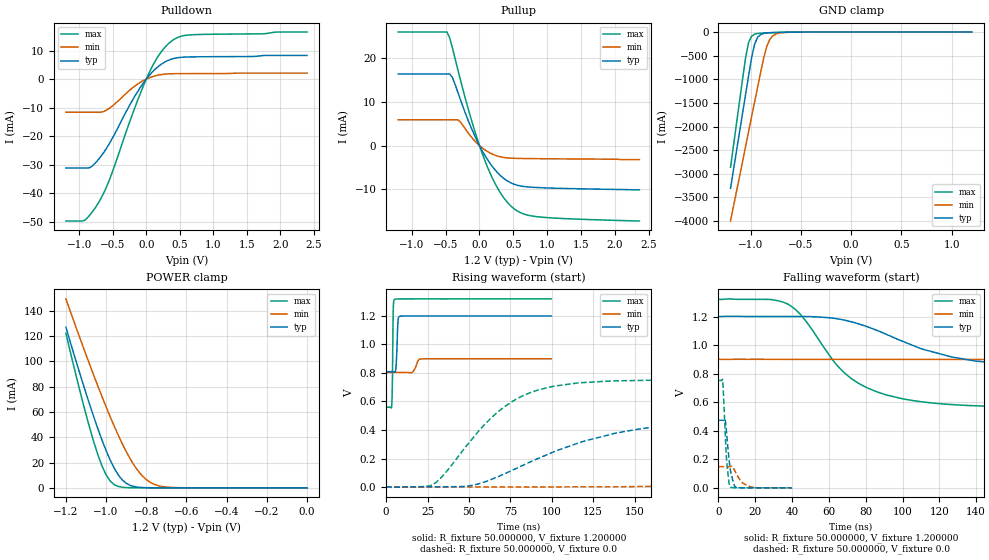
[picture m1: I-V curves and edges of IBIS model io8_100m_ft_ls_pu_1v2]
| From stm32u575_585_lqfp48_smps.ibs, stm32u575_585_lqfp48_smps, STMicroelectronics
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|   Model io8_100m_ft_ls_pu_1v2
[Model]  io8_100m_ft_ls_pu_1v2
Model_type I/O
Polarity   Non-Inverting
Enable   Active-Low
Vinl =   0.360000V
Vinh =   0.840000V
Vmeas =  0.600000V
Cref =   50.000000pF
Rref =   100.000000M
Vref =   0.0V
C_comp   2.947800pF   2.877700pF   2.996100pF
[Temperature Range]   25.000000   0.140000k   -40.000000
[Pullup Reference]   1.200000V   0.900000V   1.320000V
[Pulldown Reference]   0.0V   0.0V   0.0V
[POWER Clamp Reference]   1.200000V   0.900000V   1.320000V
[GND Clamp Reference]   0.0V   0.0V   0.0V
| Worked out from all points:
|   slope of the pulldown table from 0 to 0.18 V, typ, clamps not added: 40.7 ohm
|   slope of the pullup table from 0 to 0.18 V, typ, clamps not added: 39.5 ohm
|   GND clamp passes 1 mA (typ) near -0.51 V on its own axis
|   POWER clamp passes 1 mA (typ) near -0.86 V on its own axis
|   rising waveform, R_fixture 50.000000, V_fixture 1.200000: 20-80 % time 754ps typ, 2.06ns min, 442ps max; typ from 0.809 V to 1.2 V
|   rising waveform, R_fixture 50.000000, V_fixture 0.0: 20-80 % time 67.2ns typ, 167ns min, 37.1ns max; typ from 0.001 V to 0.474 V
|   falling waveform, R_fixture 50.000000, V_fixture 1.200000: 20-80 % time 58ns typ, 150ns min, 31.6ns max; typ from 1.2 V to 0.809 V
|   falling waveform, R_fixture 50.000000, V_fixture 0.0: 20-80 % time 2.49ns typ, 4.76ns min, 1.84ns max; typ from 0.474 V to 0.001 V
[Pulldown]
|Voltage   I(typ)   I(min)   I(max)
-1.2V     -31.16mA   -11.61mA   -49.71mA
-920mV    -31.16mA   -11.61mA   -49.49mA
-840mV    -31mA      -11.61mA   -47.54mA
-720mV    -28.32mA   -11.61mA   -43.58mA
-560mV    -22.95mA   -10.37mA   -35.89mA
-200mV    -7.146mA   -2.964mA   -11.89mA
0V        0A         0A         0A
160mV     4.047mA    1.298mA    7.361mA
360mV     6.869mA    1.87mA     13mA
480mV     7.543mA    1.91mA     14.69mA
640mV     7.765mA    1.923mA    15.46mA
2.4V      8.291mA    2.091mA    16.49mA
[Pullup]
|Voltage   I(typ)   I(min)   I(max)
-1.2V     16.38mA    5.9mA      25.96mA
-480mV    16.38mA    5.9mA      25.96mA
-440mV    16.38mA    5.9mA      24.63mA
-400mV    15.57mA    5.9mA      22.35mA
-320mV    12.21mA    5.9mA      17.37mA
-120mV    3.997mA    1.962mA    5.905mA
80mV      -2.237mA   -962.6uA   -3.434mA
280mV     -6.404mA   -2.453mA   -10.06mA
520mV     -8.88mA    -2.9mA     -14.54mA
680mV     -9.389mA   -2.951mA   -15.76mA
920mV     -9.627mA   -2.991mA   -16.35mA
2.36V     -10.1mA    -3.2mA     -17.23mA
[GND_clamp]
|Voltage   I(typ)   I(min)   I(max)
-1.2V     -3.305A    -3.998A    -2.862A
-1.05V    -1.316A    -2.418A    -539.3mA
-1.02V    -921mA     -2.103A    -218.8mA
-990mV    -539.5mA   -1.788A    -87.43mA
-960mV    -252.1mA   -1.474A    -44.36mA
-930mV    -110.5mA   -1.16A     -30.32mA
-870mV    -28.03mA   -549.1mA   -21.09mA
-840mV    -18.43mA   -305.6mA   -18.27mA
-810mV    -13.9mA    -159.7mA   -15.73mA
-780mV    -11.23mA   -82.35mA   -13.37mA
-600mV    -2.976mA   -4.272mA   -3.058mA
1.2V      0A         14.74nA    0A
[POWER_clamp]
|Voltage   I(typ)   I(min)   I(max)
-1.2V     127mA      149.4mA    122.2mA
-1.12V    84.98mA    114mA      70.29mA
-1.06V    55.52mA    88.42mA    35.69mA
-1.02V    37.64mA    72.04mA    17.19mA
-1V       29.52mA    64.13mA    10.33mA
-960mV    15.7mA     48.99mA    2.596mA
-900mV    3.636mA    28.77mA    207.8uA
-840mV    502.9uA    13.24mA    43.4uA
-800mV    129uA      6.535mA    43.4uA
-740mV    25.52uA    1.726mA    43.4uA
-620mV    25.17uA    82.33uA    35.63uA
0V        0A         17.33nA    0A
[Ramp]
| variable   typ   min   max
dV/dt_r  0.28388/67.07871n   88.97985m/0.16642u  0.45093/37.04685n
dV/dt_f  0.23430/57.90286n   57.81000m/0.15005u  0.45608/31.52964n
R_load = 50.000000
[Rising Waveform]
R_fixture= 50.000000
V_fixture= 1.200000
V_fixture_min= 0.900000
V_fixture_max= 1.320000
|time   V(typ)   V(min)   V(max)
0s        809.5mV    803.6mV    559.9mV
3.403ns   809.5mV    803.6mV    576.3mV
3.804ns   809.6mV    803.6mV    766.7mV
4.204ns   809.5mV    803.6mV    1.214V
5.005ns   806.3mV    803.6mV    1.315V
6.006ns   853.2mV    803.6mV    1.319V
7.207ns   1.173V     803.6mV    1.319V
8.208ns   1.197V     803.6mV    1.319V
21.02ns   1.2V       898.3mV    1.32V
99.7ns    1.2V       900mV      1.32V
[Rising Waveform]
R_fixture= 50.000000
V_fixture= 0.0
V_fixture_min= 0.0
V_fixture_max= 0.0
|time   V(typ)   V(min)   V(max)
0s        591.7uV    600.2uV    545.2uV
28.03ns   1.403mV    898.2uV    15.96mV
50.05ns   7.829mV    903.4uV    310.8mV
72.07ns   96.01mV    942uV      568.4mV
92.09ns   201.9mV    993.9uV    681.9mV
116.1ns   309mV      1.297mV    730.7mV
160.2ns   418.2mV    5.047mV    749mV
222.2ns   462.8mV    34.3mV     752mV
460.5ns   473.7mV    136.7mV    752.1mV
997ns     473.8mV    149mV      752.2mV
[Falling Waveform]
R_fixture= 50.000000
V_fixture= 1.200000
V_fixture_min= 0.900000
V_fixture_max= 1.320000
|time   V(typ)   V(min)   V(max)
0s        1.2V       900mV      1.32V
36.04ns   1.2V       900mV      1.296V
46.05ns   1.2V       900mV      1.191V
64.06ns   1.185V     900mV      863.5mV
76.08ns   1.149V     900mV      732.8mV
100.1ns   1.026V     900mV      624.1mV
128.1ns   913.9mV    899.6mV    582.4mV
198.2ns   830.2mV    889.5mV    562mV
274.3ns   813.4mV    852.2mV    559.9mV
997ns     809.5mV    803.6mV    559.9mV
[Falling Waveform]
R_fixture= 50.000000
V_fixture= 0.0
V_fixture_min= 0.0
V_fixture_max= 0.0
|time   V(typ)   V(min)   V(max)
0s        473.8mV    149mV      752.2mV
2.242ns   473.8mV    149mV      757mV
3.604ns   480.9mV    149mV      396.8mV
4.324ns   394.5mV    149mV      212.5mV
6.166ns   151.3mV    149.2mV    9.71mV
8.328ns   26.81mV    133.3mV    1.743mV
9.61ns    2.695mV    100.9mV    1.279mV
13.13ns   887.8uV    34.86mV    1.037mV
18.9ns    590.7uV    3.478mV    1.034mV
39.88ns   591.7uV    600.2uV    545.2uV
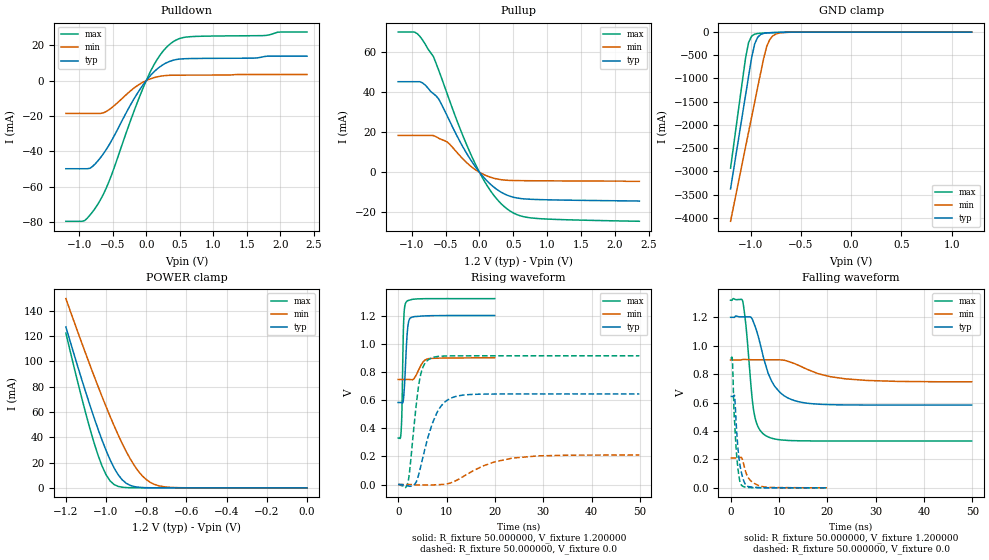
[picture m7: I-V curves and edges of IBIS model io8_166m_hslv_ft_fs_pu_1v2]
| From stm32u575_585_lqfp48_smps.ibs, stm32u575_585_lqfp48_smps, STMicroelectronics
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|   Model io8_166m_hslv_ft_fs_pu_1v2
[Model]  io8_166m_hslv_ft_fs_pu_1v2
Model_type I/O
Polarity   Non-Inverting
Enable   Active-Low
Vinl =   0.360000V
Vinh =   0.840000V
Vmeas =  0.600000V
Cref =   50.000000pF
Rref =   100.000000M
Vref =   0.0V
C_comp   3.151700pF   3.087200pF   3.197900pF
[Temperature Range]   25.000000   0.140000k   -40.000000
[Pullup Reference]   1.200000V   0.900000V   1.320000V
[Pulldown Reference]   0.0V   0.0V   0.0V
[POWER Clamp Reference]   1.200000V   0.900000V   1.320000V
[GND Clamp Reference]   0.0V   0.0V   0.0V
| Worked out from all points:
|   slope of the pulldown table from 0 to 0.18 V, typ, clamps not added: 25.4 ohm
|   slope of the pullup table from 0 to 0.18 V, typ, clamps not added: 27.8 ohm
|   GND clamp passes 1 mA (typ) near -0.51 V on its own axis
|   POWER clamp passes 1 mA (typ) near -0.86 V on its own axis
|   rising waveform, R_fixture 50.000000, V_fixture 1.200000: 20-80 % time 569ps typ, 1.41ns min, 325ps max; typ from 0.583 V to 1.2 V
|   rising waveform, R_fixture 50.000000, V_fixture 0.0: 20-80 % time 3.42ns typ, 8.16ns min, 1.74ns max; typ from 0 V to 0.643 V
|   falling waveform, R_fixture 50.000000, V_fixture 1.200000: 20-80 % time 3.7ns typ, 8.16ns min, 1.63ns max; typ from 1.2 V to 0.583 V
|   falling waveform, R_fixture 50.000000, V_fixture 0.0: 20-80 % time 1.04ns typ, 1.74ns min, 837ps max; typ from 0.643 V to 0 V
[Pulldown]
|Voltage   I(typ)   I(min)   I(max)
-1.2V     -49.86mA   -18.57mA   -79.56mA
-920mV    -49.86mA   -18.57mA   -79.19mA
-840mV    -49.6mA    -18.57mA   -76.08mA
-720mV    -45.32mA   -18.57mA   -69.74mA
-560mV    -36.71mA   -16.58mA   -57.44mA
-200mV    -11.43mA   -4.74mA    -19.03mA
0V        0A         0A         0A
160mV     6.477mA    2.075mA    11.78mA
360mV     10.99mA    2.99mA     20.81mA
480mV     12.07mA    3.054mA    23.52mA
640mV     12.43mA    3.075mA    24.76mA
2.4V      13.77mA    3.425mA    27.43mA
[Pullup]
|Voltage   I(typ)   I(min)   I(max)
-1.2V     45.31mA    18.46mA    70.13mA
-920mV    45.31mA    18.46mA    69.35mA
-840mV    44.69mA    18.46mA    66.15mA
-680mV    39.29mA    18.37mA    57.85mA
-600mV    36.51mA    16.99mA    50.82mA
-480mV    28.42mA    15.26mA    39.5mA
-280mV    14.84mA    7.943mA    21.22mA
-80mV     3.667mA    1.75mA     5.47mA
160mV     -5.889mA   -2.43mA    -9.115mA
400mV     -11.31mA   -3.958mA   -18.11mA
800mV     -13.54mA   -4.214mA   -22.92mA
2.36V     -14.4mA    -4.5mA     -24.47mA
[GND_clamp]
|Voltage   I(typ)   I(min)   I(max)
-1.2V     -3.379A    -4.076A    -2.932A
-1.05V    -1.35A     -2.47A     -550.7mA
-1.02V    -947.8mA   -2.149A    -221.5mA
-990mV    -552.4mA   -1.829A    -88.44mA
-960mV    -255.3mA   -1.51A     -44.87mA
-930mV    -111.8mA   -1.191A    -30.68mA
-870mV    -28.36mA   -564.6mA   -21.34mA
-840mV    -18.65mA   -309.5mA   -18.49mA
-810mV    -14.07mA   -161.6mA   -15.92mA
-780mV    -11.37mA   -83.33mA   -13.53mA
-600mV    -3.009mA   -4.322mA   -3.091mA
1.2V      0A         13.65nA    0A
[POWER_clamp]
|Voltage   I(typ)   I(min)   I(max)
-1.2V     127mA      149.4mA    122.2mA
-1.12V    84.98mA    114mA      70.29mA
-1.06V    55.52mA    88.42mA    35.69mA
-1.02V    37.64mA    72.04mA    17.19mA
-1V       29.52mA    64.13mA    10.33mA
-960mV    15.7mA     48.99mA    2.596mA
-900mV    3.636mA    28.77mA    207.8uA
-840mV    502.9uA    13.24mA    43.19uA
-800mV    129uA      6.535mA    43.19uA
-740mV    26.51uA    1.726mA    43.19uA
-620mV    25.02uA    82.33uA    35.3uA
0V        0A         17.36nA    0A
[Ramp]
| variable   typ   min   max
dV/dt_r  0.38568/3.41580n   0.12559/8.14468n   0.54818/1.73558n
dV/dt_f  0.37042/3.69164n   92.26200m/8.16858n  0.59405/1.62130n
R_load = 50.000000
[Rising Waveform]
R_fixture= 50.000000
V_fixture= 1.200000
V_fixture_min= 0.900000
V_fixture_max= 1.320000
|time   V(typ)   V(min)   V(max)
0s        582.7mV    746.1mV    330mV
640.6ps   582.6mV    746.1mV    402.8mV
800.8ps   580.1mV    746.1mV    577.7mV
1.121ns   620.5mV    746.1mV    1.151V
1.321ns   718.8mV    746.1mV    1.258V
1.682ns   974.8mV    746.1mV    1.297V
2.122ns   1.151V     746.2mV    1.307V
2.923ns   1.189V     744.4mV    1.315V
6.206ns   1.198V     893.4mV    1.32V
19.94ns   1.2V       900mV      1.32V
[Rising Waveform]
R_fixture= 50.000000
V_fixture= 0.0
V_fixture_min= 0.0
V_fixture_max= 0.0
|time   V(typ)   V(min)   V(max)
0s        428.4uV    495.8uV    346.1uV
2.002ns   -8.305mV   491.6uV    13.96mV
3.504ns   7.144mV    -2.282mV   494mV
4.404ns   93.79mV    -2.345mV   741mV
5.205ns   208.9mV    -2.243mV   840.7mV
6.406ns   363.8mV    -2.382mV   890.3mV
8.909ns   559.4mV    648.3uV    911.4mV
12.51ns   630.3mV    38.83mV    913.9mV
23.52ns   643.2mV    187.6mV    914.2mV
49.85ns   643.4mV    210mV      914.2mV
[Falling Waveform]
R_fixture= 50.000000
V_fixture= 1.200000
V_fixture_min= 0.900000
V_fixture_max= 1.320000
|time   V(typ)   V(min)   V(max)
0s        1.2V       900mV      1.32V
2.503ns   1.203V     903.1mV    1.315V
3.203ns   1.203V     903.2mV    1.135V
4.805ns   1.16V      901.1mV    539.5mV
5.706ns   1.068V     901mV      428.8mV
7.307ns   859.1mV    901mV      366.8mV
10.31ns   668.3mV    900.5mV    338mV
15.02ns   599.8mV    847.1mV    330.7mV
23.92ns   583.7mV    766.5mV    330mV
49.85ns   582.7mV    746.1mV    330mV
[Falling Waveform]
R_fixture= 50.000000
V_fixture= 0.0
V_fixture_min= 0.0
V_fixture_max= 0.0
|time   V(typ)   V(min)   V(max)
0s        643.4mV    210mV      914.2mV
400.4ps   643.4mV    210mV      887.3mV
680.7ps   648.5mV    210.1mV    574.1mV
840.8ps   644.5mV    210.1mV    463.1mV
1.161ns   457.8mV    210.1mV    274.8mV
1.481ns   298mV      209.9mV    151.6mV
2.242ns   108.9mV    214.4mV    20.07mV
3.684ns   9.259mV    70.68mV    2.667mV
5.806ns   2.533mV    16.98mV    893.4uV
19.94ns   428.4uV    495.8uV    346.1uV
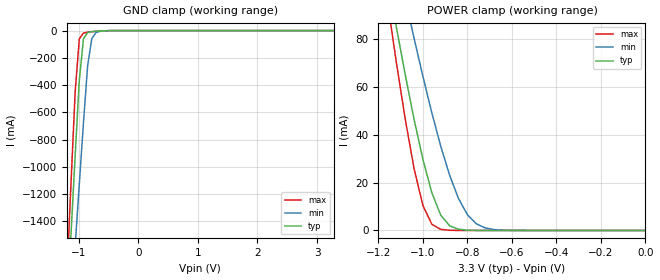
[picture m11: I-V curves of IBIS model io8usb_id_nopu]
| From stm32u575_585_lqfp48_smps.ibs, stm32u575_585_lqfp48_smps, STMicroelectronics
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|   Model io8usb_id_nopu
[Model]  io8usb_id_nopu
Model_type Input
Polarity   Inverting
Vinl =   0.990000V
Vinh =   2.310000V
C_comp   2.806600pF   2.789500pF   2.832700pF
[Temperature Range]   25.000000   0.140000k   -40.000000
[Pullup Reference]   3.300000V   2.700000V   3.600000V
[Pulldown Reference]   0.0V   0.0V   0.0V
[POWER Clamp Reference]   3.300000V   2.700000V   3.600000V
[GND Clamp Reference]   0.0V   0.0V   0.0V
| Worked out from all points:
|   GND clamp passes 1 mA (typ) near -0.54 V on its own axis
|   POWER clamp passes 1 mA (typ) near -0.85 V on its own axis
[GND_clamp]
|Voltage   I(typ)   I(min)   I(max)
-3.3V     -9.738A    -9.661A    -9.429A
-1.2V     -2.082A    -2.5A      -1.818A
-1.13V    -1.502A    -2.042A    -1.132A
-1.06V    -925mA     -1.585A    -457.2mA
-990mV    -365.8mA   -1.129A    -60.2mA
-920mV    -59.59mA   -677.3mA   -18.21mA
-850mV    -14.46mA   -258.1mA   -12.36mA
-780mV    -7.59mA    -59.03mA   -8.629mA
-710mV    -4.8mA     -14.88mA   -5.493mA
-640mV    -2.824mA   -5.051mA   -3.017mA
-360mV    -19.06uA   -107.3uA   -5.16uA
3.28V     0A         7.911nA    -6.821nA
[POWER_clamp]
|Voltage   I(typ)   I(min)   I(max)
-3.28V    1.355A     1.167A     1.664A
-1.16V    105.7mA    131.6mA    95.69mA
-1.12V    84.97mA    114mA      70.27mA
-1.08V    65.05mA    96.83mA    46.54mA
-1.04V    46.34mA    80.15mA    25.76mA
-1V       29.51mA    64.13mA    10.3mA
-960mV    15.69mA    48.99mA    2.571mA
-920mV    6.373mA    35.1mA     455.6uA
-840mV    490.7uA    13.24mA    11.36uA
-760mV    27.33uA    2.767mA    276.7nA
-640mV    346.5nA    134.1uA    98.1nA
0V        0A         12.56nA    0A
